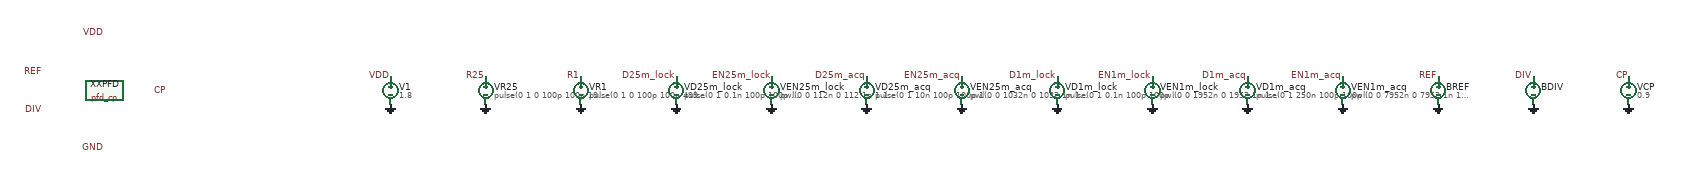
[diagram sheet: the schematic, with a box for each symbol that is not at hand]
v {xschem version=3.4.7 file_version=1.2
* tb_power_pfd_cp.sch -- sky130 pfd_cp supply-current campaign (issue #233)
* GENERATED by sim/power/build.py from its stage table; do not hand-edit.
*
* design/pfd-cp/pfd_cp.sch with ideal REF/DIV trains and CP held at 0.9 V by an ideal source (VCP): the charge-pump output current is drawn from V1 on UP and returned to GND on DN, so i(V1) includes the pump's delivered current; the loop filter is not present.
*
* V1 is the ONLY supply source on the DUT's VDD net, so i(V1) is the block's
* own supply current. The stimulus (staged sources, idle stage first) is the
* drawn stimulus sources; sim/power/testbench/pfd-cp.stages.json is the
* machine-readable stage table the reducer uses.
*
* Provenance: adapted from sim/vco-supply-pushing/testbench/tb_vco_pushing.sch
* (this repo, issue #165): same label-pin wiring, V1 supply, DUT instance style.
}
G {}
V {}
S {}
E {}

C {design/pfd-cp/pfd_cp.sym} 0 0 0 0 {name=XXPFD}
C {devices/lab_pin.sym} 0 -120 0 0 {name=p1 sig_type=std_logic lab=VDD}
C {devices/lab_pin.sym} 0 120 0 0 {name=p2 sig_type=std_logic lab=GND}
C {devices/lab_pin.sym} -130 -40 0 0 {name=p3 sig_type=std_logic lab=REF}
C {devices/lab_pin.sym} -130 40 0 0 {name=p4 sig_type=std_logic lab=DIV}
C {devices/lab_pin.sym} 130 0 0 0 {name=p5 sig_type=std_logic lab=CP}
C {devices/vsource.sym} 600 0 0 0 {name=V1 value=1.8 savecurrent=false}
C {devices/lab_pin.sym} 600 -30 0 0 {name=pv1 sig_type=std_logic lab=VDD}
C {devices/gnd.sym} 600 30 0 0 {name=lg1 lab=GND}
C {devices/vsource.sym} 800 0 0 0 {name=VR25 value="pulse(0 1 0 100p 100p 19.9n 40n)" savecurrent=false}
C {devices/lab_pin.sym} 800 -30 0 0 {name=ps1 sig_type=std_logic lab=R25}
C {devices/gnd.sym} 800 30 0 0 {name=lgs1 lab=GND}
C {devices/vsource.sym} 1000 0 0 0 {name=VR1 value="pulse(0 1 0 100p 100p 499.9n 1000n)" savecurrent=false}
C {devices/lab_pin.sym} 1000 -30 0 0 {name=ps2 sig_type=std_logic lab=R1}
C {devices/gnd.sym} 1000 30 0 0 {name=lgs2 lab=GND}
C {devices/vsource.sym} 1200 0 0 0 {name=VD25m_lock value="pulse(0 1 0.1n 100p 100p 19.9n 40n)" savecurrent=false}
C {devices/lab_pin.sym} 1200 -30 0 0 {name=ps3 sig_type=std_logic lab=D25m_lock}
C {devices/gnd.sym} 1200 30 0 0 {name=lgs3 lab=GND}
C {devices/vsource.sym} 1400 0 0 0 {name=VEN25m_lock value="pwl(0 0 112n 0 112.1n 1 1032n 1 1032.1n 0)" savecurrent=false}
C {devices/lab_pin.sym} 1400 -30 0 0 {name=ps4 sig_type=std_logic lab=EN25m_lock}
C {devices/gnd.sym} 1400 30 0 0 {name=lgs4 lab=GND}
C {devices/vsource.sym} 1600 0 0 0 {name=VD25m_acq value="pulse(0 1 10n 100p 100p 19.9n 40n)" savecurrent=false}
C {devices/lab_pin.sym} 1600 -30 0 0 {name=ps5 sig_type=std_logic lab=D25m_acq}
C {devices/gnd.sym} 1600 30 0 0 {name=lgs5 lab=GND}
C {devices/vsource.sym} 1800 0 0 0 {name=VEN25m_acq value="pwl(0 0 1032n 0 1032.1n 1 1952n 1 1952.1n 0)" savecurrent=false}
C {devices/lab_pin.sym} 1800 -30 0 0 {name=ps6 sig_type=std_logic lab=EN25m_acq}
C {devices/gnd.sym} 1800 30 0 0 {name=lgs6 lab=GND}
C {devices/vsource.sym} 2000 0 0 0 {name=VD1m_lock value="pulse(0 1 0.1n 100p 100p 499.9n 1000n)" savecurrent=false}
C {devices/lab_pin.sym} 2000 -30 0 0 {name=ps7 sig_type=std_logic lab=D1m_lock}
C {devices/gnd.sym} 2000 30 0 0 {name=lgs7 lab=GND}
C {devices/vsource.sym} 2200 0 0 0 {name=VEN1m_lock value="pwl(0 0 1952n 0 1952.1n 1 7952n 1 7952.1n 0)" savecurrent=false}
C {devices/lab_pin.sym} 2200 -30 0 0 {name=ps8 sig_type=std_logic lab=EN1m_lock}
C {devices/gnd.sym} 2200 30 0 0 {name=lgs8 lab=GND}
C {devices/vsource.sym} 2400 0 0 0 {name=VD1m_acq value="pulse(0 1 250n 100p 100p 499.9n 1000n)" savecurrent=false}
C {devices/lab_pin.sym} 2400 -30 0 0 {name=ps9 sig_type=std_logic lab=D1m_acq}
C {devices/gnd.sym} 2400 30 0 0 {name=lgs9 lab=GND}
C {devices/vsource.sym} 2600 0 0 0 {name=VEN1m_acq value="pwl(0 0 7952n 0 7952.1n 1 13952n 1 13952.1n 0)" savecurrent=false}
C {devices/lab_pin.sym} 2600 -30 0 0 {name=ps10 sig_type=std_logic lab=EN1m_acq}
C {devices/gnd.sym} 2600 30 0 0 {name=lgs10 lab=GND}
C {devices/bsource.sym} 2800 0 0 0 {name=BREF VAR=V FUNC="v(VDD)*(v(R25)*(v(EN25m_lock)+v(EN25m_acq))+v(R1)*(v(EN1m_lock)+v(EN1m_acq)))" m=1}
C {devices/lab_pin.sym} 2800 -30 0 0 {name=ps11 sig_type=std_logic lab=REF}
C {devices/gnd.sym} 2800 30 0 0 {name=lgs11 lab=GND}
C {devices/bsource.sym} 3000 0 0 0 {name=BDIV VAR=V FUNC="v(VDD)*(v(D25m_lock)*v(EN25m_lock)+v(D25m_acq)*v(EN25m_acq)+v(D1m_lock)*v(EN1m_lock)+v(D1m_acq)*v(EN1m_acq))" m=1}
C {devices/lab_pin.sym} 3000 -30 0 0 {name=ps12 sig_type=std_logic lab=DIV}
C {devices/gnd.sym} 3000 30 0 0 {name=lgs12 lab=GND}
C {devices/vsource.sym} 3200 0 0 0 {name=VCP value="0.9" savecurrent=false}
C {devices/lab_pin.sym} 3200 -30 0 0 {name=ps13 sig_type=std_logic lab=CP}
C {devices/gnd.sym} 3200 30 0 0 {name=lgs13 lab=GND}
C {devices/title.sym} -200 500 0 0 {name=lt author="2AM Logic (issue #233, sky130 pfd_cp supply-current campaign)"}
